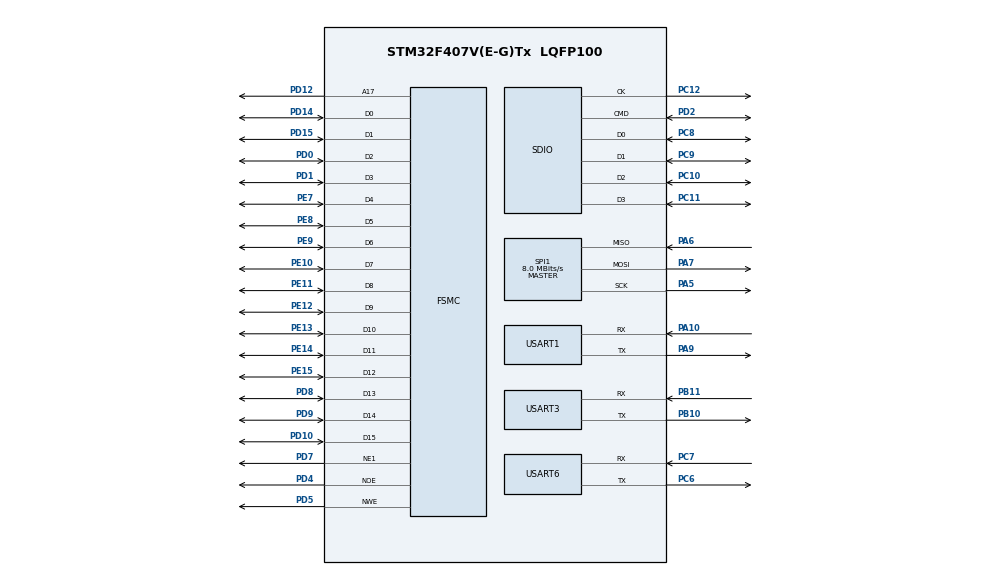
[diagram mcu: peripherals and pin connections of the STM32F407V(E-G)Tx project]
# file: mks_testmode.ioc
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Dma.Request0=SDIO
Dma.SDIO.0.Direction=DMA_PERIPH_TO_MEMORY
Dma.SDIO.0.FIFOMode=DMA_FIFOMODE_ENABLE
Dma.SDIO.0.FIFOThreshold=DMA_FIFO_THRESHOLD_FULL
Dma.SDIO.0.Instance=DMA2_Stream3
Dma.SDIO.0.MemBurst=DMA_MBURST_INC4
Dma.SDIO.0.MemDataAlignment=DMA_MDATAALIGN_WORD
Dma.SDIO.0.MemInc=DMA_MINC_ENABLE
Dma.SDIO.0.Mode=DMA_PFCTRL
Dma.SDIO.0.PeriphBurst=DMA_PBURST_INC4
Dma.SDIO.0.PeriphDataAlignment=DMA_PDATAALIGN_WORD
Dma.SDIO.0.PeriphInc=DMA_PINC_DISABLE
Dma.SDIO.0.Priority=DMA_PRIORITY_LOW
FSMC.ExtendedMode1=FSMC_EXTENDED_MODE_DISABLE
Mcu.Family=STM32F4
Mcu.Name=STM32F407V(E-G)Tx
Mcu.Package=LQFP100
NVIC.DMA2_Stream3_IRQn=true\:0\:0\:false\:false\:true\:false\:true
NVIC.PriorityGroup=NVIC_PRIORITYGROUP_4
PA10.Mode=Asynchronous
PA10.Signal=USART1_RX
PA5.Mode=Full_Duplex_Master
PA5.Signal=SPI1_SCK
PA6.Mode=Full_Duplex_Master
PA6.Signal=SPI1_MISO
PA7.Mode=Full_Duplex_Master
PA7.Signal=SPI1_MOSI
PA9.Mode=Asynchronous
PA9.Signal=USART1_TX
PB10.Mode=Asynchronous
PB10.Signal=USART3_TX
PB11.Mode=Asynchronous
PB11.Signal=USART3_RX
PC10.Mode=SD_4_bits_Wide_bus
PC10.Signal=SDIO_D2
PC11.Mode=SD_4_bits_Wide_bus
PC11.Signal=SDIO_D3
PC12.Mode=SD_4_bits_Wide_bus
PC12.Signal=SDIO_CK
PC6.Mode=Asynchronous
PC6.Signal=USART6_TX
PC7.Mode=Asynchronous
PC7.Signal=USART6_RX
PC8.Mode=SD_4_bits_Wide_bus
PC8.Signal=SDIO_D0
PC9.Mode=SD_4_bits_Wide_bus
PC9.Signal=SDIO_D1
PD0.Mode=16b-d1
PD0.Signal=FSMC_D2
PD1.Mode=16b-d1
PD1.Signal=FSMC_D3
PD10.Mode=16b-d1
PD10.Signal=FSMC_D15
PD12.Mode=A17_1
PD12.Signal=FSMC_A17
PD14.Mode=16b-d1
PD14.Signal=FSMC_D0
PD15.Mode=16b-d1
PD15.Signal=FSMC_D1
PD2.Mode=SD_4_bits_Wide_bus
PD2.Signal=SDIO_CMD
PD4.Mode=Lcd1
PD4.Signal=FSMC_NOE
PD5.Mode=Lcd1
PD5.Signal=FSMC_NWE
PD7.Mode=NorPsramChipSelect1_1
PD7.Signal=FSMC_NE1
PD8.Mode=16b-d1
PD8.Signal=FSMC_D13
PD9.Mode=16b-d1
PD9.Signal=FSMC_D14
PE10.Mode=16b-d1
PE10.Signal=FSMC_D7
PE11.Mode=16b-d1
PE11.Signal=FSMC_D8
PE12.Mode=16b-d1
PE12.Signal=FSMC_D9
PE13.Mode=16b-d1
PE13.Signal=FSMC_D10
PE14.Mode=16b-d1
PE14.Signal=FSMC_D11
PE15.Mode=16b-d1
PE15.Signal=FSMC_D12
PE7.Mode=16b-d1
PE7.Signal=FSMC_D4
PE8.Mode=16b-d1
PE8.Signal=FSMC_D5
PE9.Mode=16b-d1
PE9.Signal=FSMC_D6
PH0-OSC_IN.Mode=HSE-External-Oscillator
PH0-OSC_IN.Signal=RCC_OSC_IN
PH1-OSC_OUT.Mode=HSE-External-Oscillator
PH1-OSC_OUT.Signal=RCC_OSC_OUT
ProjectManager.HeapSize=0x200
ProjectManager.StackSize=0x400
ProjectManager.TargetToolchain=Makefile
RCC.AHBFreq_Value=16000000
RCC.APB1Freq_Value=16000000
RCC.APB2Freq_Value=16000000
RCC.CortexFreq_Value=16000000
RCC.HSE_VALUE=25000000
RCC.HSI_VALUE=16000000
RCC.SYSCLKFreq_VALUE=16000000
RCC.VCOOutputFreq_Value=192000000
SPI1.CalculateBaudRate=8.0 MBits/s
SPI1.Direction=SPI_DIRECTION_2LINES
SPI1.Mode=SPI_MODE_MASTER
SPI1.VirtualType=VM_MASTER
USART1.VirtualMode=VM_ASYNC
USART3.VirtualMode=VM_ASYNC
USART6.VirtualMode=VM_ASYNC
board=custom

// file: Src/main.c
#include "main.h"
#include "stm32_adafruit_lcd.h"
#include "stm32_adafruit_ts.h"
#include "ts.h"
#include "lcd_screen.h"
#include <XPT2046_touch.h>
SD_HandleTypeDef hsd;
DMA_HandleTypeDef hdma_sdio;

SPI_HandleTypeDef hspi1;

UART_HandleTypeDef huart1;
UART_HandleTypeDef huart3;
UART_HandleTypeDef huart6;

SRAM_HandleTypeDef hsram1;

TIM_HandleTypeDef htim6;

void SystemClock_Config(void);
static void MX_GPIO_Init(void);
static void MX_DMA_Init(void);
static void MX_FSMC_Init(void);
static void MX_SDIO_SD_Init(void);
static void MX_SPI1_Init(void);
static void MX_USART1_UART_Init(void);
static void MX_USART3_UART_Init(void);
static void MX_USART6_UART_Init(void);

#define LCD_INIT_CLEAR 1

 #define TEXT "testing"

 //Vars
 char txt[60];

#define FONT_USED Font8

char X_POS;
uint16_t tsx, tsy, dx, dy, c;

void display_line_numbers(void)
{
 // BSP_LCD_Clear(LCD_COLOR_BLACK);
 //Display Line numbers
  for (int line_nr=1;line_nr<27;line_nr++)
    {
      BSP_LCD_SetTextColor(LCD_COLOR_BLACK);
      snprintf(txt, 60,"");
      BSP_LCD_DisplayStringAt(0,BSP_LCD_GetYSize()-(line_nr * CHARSIZEY),(uint8_t *)txt,CENTER_MODE);

      BSP_LCD_SetTextColor(LCD_COLOR_RED+(line_nr*1));
      snprintf(txt, 60, "   Touch X %d,Touch Y %d,State %d ",dx,dy, XPT2046_TouchPressed());
      BSP_LCD_DisplayStringAt(0,BSP_LCD_GetYSize()-(line_nr * CHARSIZEY),(uint8_t *)txt,CENTER_MODE);

   }
}

char SECOND_COUNT=0;
char REFRESH=0;

int main(void)
{

  HAL_Init();
  SystemClock_Config();

  MX_GPIO_Init();
  MX_DMA_Init();
  MX_FSMC_Init();
  MX_SDIO_SD_Init();
  MX_SPI1_Init();
  MX_USART1_UART_Init();
  MX_USART3_UART_Init();
  MX_USART6_UART_Init();

  int error_lcd = BSP_LCD_Init();
  if (error_lcd != LCD_OK )
  {
    printf("lcd error %d",error_lcd);
  }

  BSP_LCD_SetTextColor(LCD_COLOR_RED);
  BSP_LCD_SetFont(&Font12);
  //Beyond Here there be dragons and main code
  //mainApp();
mainApp();
  while (1)
  {
  HAL_Delay(100);
  if(XPT2046_TouchPressed()) {

    XPT2046_TouchGetCoordinates(&dx,&dy);

  }
  if (REFRESH>10)
  {
  // display_line_numbers();
    REFRESH=0;
  }
  if (SECOND_COUNT>200)
  {
    X_POS++;
    SECOND_COUNT=0;
  }
  SECOND_COUNT++;
  REFRESH++;
  display_line_numbers();
  }

}

void SystemClock_Config(void)
{
  RCC_OscInitTypeDef RCC_OscInitStruct;
 RCC_ClkInitTypeDef RCC_ClkInitStruct;
 RCC_PeriphCLKInitTypeDef PeriphClkInitStruct;

    /**Configure the main internal regulator output voltage
    */
  __HAL_RCC_PWR_CLK_ENABLE();

  __HAL_PWR_VOLTAGESCALING_CONFIG(PWR_REGULATOR_VOLTAGE_SCALE1);

    /**Initializes the CPU, AHB and APB busses clocks
    */
  RCC_OscInitStruct.OscillatorType = RCC_OSCILLATORTYPE_HSE;
  RCC_OscInitStruct.HSEState = RCC_HSE_ON;
  RCC_OscInitStruct.PLL.PLLState = RCC_PLL_ON;
  RCC_OscInitStruct.PLL.PLLSource = RCC_PLLSOURCE_HSE;
  RCC_OscInitStruct.PLL.PLLM = 4;
  RCC_OscInitStruct.PLL.PLLN = 168;
  RCC_OscInitStruct.PLL.PLLP = RCC_PLLP_DIV2;
  RCC_OscInitStruct.PLL.PLLQ = 7;
  if (HAL_RCC_OscConfig(&RCC_OscInitStruct) != HAL_OK)
  {
    Error_Handler();
  }

    /**Initializes the CPU, AHB and APB busses clocks
    */
  RCC_ClkInitStruct.ClockType = RCC_CLOCKTYPE_HCLK|RCC_CLOCKTYPE_SYSCLK
                              |RCC_CLOCKTYPE_PCLK1|RCC_CLOCKTYPE_PCLK2;
  RCC_ClkInitStruct.SYSCLKSource = RCC_SYSCLKSOURCE_PLLCLK;
  RCC_ClkInitStruct.AHBCLKDivider = RCC_SYSCLK_DIV1;
  RCC_ClkInitStruct.APB1CLKDivider = RCC_HCLK_DIV4;
  RCC_ClkInitStruct.APB2CLKDivider = RCC_HCLK_DIV2;

  if (HAL_RCC_ClockConfig(&RCC_ClkInitStruct, FLASH_LATENCY_5) != HAL_OK)
  {
    Error_Handler();
  }

  PeriphClkInitStruct.PeriphClockSelection = RCC_PERIPHCLK_RTC;
  PeriphClkInitStruct.RTCClockSelection = RCC_RTCCLKSOURCE_LSI;
  if (HAL_RCCEx_PeriphCLKConfig(&PeriphClkInitStruct) != HAL_OK)
  {
    Error_Handler();
  }

    /**Configure the Systick interrupt time
    */
  HAL_SYSTICK_Config(HAL_RCC_GetHCLKFreq()/1000);

    /**Configure the Systick
    */
  HAL_SYSTICK_CLKSourceConfig(SYSTICK_CLKSOURCE_HCLK);

  /* SysTick_IRQn interrupt configuration */
  HAL_NVIC_SetPriority(SysTick_IRQn, 0, 0);
}

static void MX_SDIO_SD_Init(void)
{

  hsd.Instance = SDIO;
  hsd.Init.ClockEdge = SDIO_CLOCK_EDGE_RISING;
  hsd.Init.ClockBypass = SDIO_CLOCK_BYPASS_DISABLE;
  hsd.Init.ClockPowerSave = SDIO_CLOCK_POWER_SAVE_DISABLE;
  hsd.Init.BusWide = SDIO_BUS_WIDE_1B;
  hsd.Init.HardwareFlowControl = SDIO_HARDWARE_FLOW_CONTROL_DISABLE;
  hsd.Init.ClockDiv = 0;
  if (HAL_SD_Init(&hsd) != HAL_OK)
  {
    Error_Handler();
  }
  if (HAL_SD_ConfigWideBusOperation(&hsd, SDIO_BUS_WIDE_4B) != HAL_OK)
  {
    Error_Handler();
  }

}

static void MX_SPI1_Init(void)
{

  hspi1.Instance = SPI1;
  hspi1.Init.Mode = SPI_MODE_MASTER;
  hspi1.Init.Direction = SPI_DIRECTION_2LINES;
  hspi1.Init.DataSize = SPI_DATASIZE_8BIT;
  hspi1.Init.CLKPolarity = SPI_POLARITY_LOW;
  hspi1.Init.CLKPhase = SPI_PHASE_1EDGE;
  hspi1.Init.NSS = SPI_NSS_SOFT;
  hspi1.Init.BaudRatePrescaler = SPI_BAUDRATEPRESCALER_256;
  hspi1.Init.FirstBit = SPI_FIRSTBIT_MSB;
  hspi1.Init.TIMode = SPI_TIMODE_DISABLE;
  hspi1.Init.CRCCalculation = SPI_CRCCALCULATION_DISABLE;
  hspi1.Init.CRCPolynomial = 10;
  if (HAL_SPI_Init(&hspi1) != HAL_OK)
  {
    Error_Handler();
  }

}

static void MX_USART1_UART_Init(void)
{

  huart1.Instance = USART1;
  huart1.Init.BaudRate = 115200;
  huart1.Init.WordLength = UART_WORDLENGTH_8B;
  huart1.Init.StopBits = UART_STOPBITS_1;
  huart1.Init.Parity = UART_PARITY_NONE;
  huart1.Init.Mode = UART_MODE_TX_RX;
  huart1.Init.HwFlowCtl = UART_HWCONTROL_NONE;
  huart1.Init.OverSampling = UART_OVERSAMPLING_16;
  if (HAL_UART_Init(&huart1) != HAL_OK)
  {
    Error_Handler();
  }

}

static void MX_USART3_UART_Init(void)
{

  huart3.Instance = USART3;
  huart3.Init.BaudRate = 115200;
  huart3.Init.WordLength = UART_WORDLENGTH_8B;
  huart3.Init.StopBits = UART_STOPBITS_1;
  huart3.Init.Parity = UART_PARITY_NONE;
  huart3.Init.Mode = UART_MODE_TX_RX;
  huart3.Init.HwFlowCtl = UART_HWCONTROL_NONE;
  huart3.Init.OverSampling = UART_OVERSAMPLING_16;
  if (HAL_UART_Init(&huart3) != HAL_OK)
  {
    Error_Handler();
  }

}

static void MX_USART6_UART_Init(void)
{

  huart6.Instance = USART6;
  huart6.Init.BaudRate = 115200;
  huart6.Init.WordLength = UART_WORDLENGTH_8B;
  huart6.Init.StopBits = UART_STOPBITS_1;
  huart6.Init.Parity = UART_PARITY_NONE;
  huart6.Init.Mode = UART_MODE_TX_RX;
  huart6.Init.HwFlowCtl = UART_HWCONTROL_NONE;
  huart6.Init.OverSampling = UART_OVERSAMPLING_16;
  if (HAL_UART_Init(&huart6) != HAL_OK)
  {
    Error_Handler();
  }

}

static void MX_DMA_Init(void)
{

  /* DMA controller clock enable */
  __HAL_RCC_DMA2_CLK_ENABLE();

  /* DMA interrupt init */
  /* DMA2_Stream3_IRQn interrupt configuration */
  HAL_NVIC_SetPriority(DMA2_Stream3_IRQn, 0, 0);
  HAL_NVIC_EnableIRQ(DMA2_Stream3_IRQn);

}

static void MX_GPIO_Init(void)
{
GPIO_InitTypeDef GPIO_InitStruct = {0};
  /* GPIO Ports Clock Enable */
  __HAL_RCC_GPIOH_CLK_ENABLE();
  __HAL_RCC_GPIOA_CLK_ENABLE();
  __HAL_RCC_GPIOE_CLK_ENABLE();
  __HAL_RCC_GPIOB_CLK_ENABLE();
  __HAL_RCC_GPIOD_CLK_ENABLE();
  __HAL_RCC_GPIOC_CLK_ENABLE();

 /*Configure GPIO pin Output Level */
  HAL_GPIO_WritePin(GPIOA, GPIO_PIN_1, GPIO_PIN_RESET);

  /*Configure GPIO pin Output Level */
  HAL_GPIO_WritePin(GPIOB, GPIO_PIN_0, GPIO_PIN_RESET);

  /*Configure GPIO pin : PA1 */
  GPIO_InitStruct.Pin = GPIO_PIN_1|GPIO_PIN_2;
  GPIO_InitStruct.Mode = GPIO_MODE_OUTPUT_PP;
  GPIO_InitStruct.Pull = GPIO_NOPULL;
  GPIO_InitStruct.Speed = GPIO_SPEED_FREQ_LOW;
  HAL_GPIO_Init(GPIOA, &GPIO_InitStruct);

  /*Configure GPIO pin : PB0 */
  GPIO_InitStruct.Pin = GPIO_PIN_0| GPIO_PIN_9;
  GPIO_InitStruct.Mode = GPIO_MODE_OUTPUT_PP;
  GPIO_InitStruct.Pull = GPIO_PULLUP;
  GPIO_InitStruct.Speed = GPIO_SPEED_FREQ_LOW;
  HAL_GPIO_Init(GPIOB, &GPIO_InitStruct);

  //Configure TP_INT Pin
 GPIO_InitStruct.Pin = GPIO_PIN_5;
 GPIO_InitStruct.Mode = GPIO_MODE_INPUT;
 GPIO_InitStruct.Pull = GPIO_NOPULL;
 GPIO_InitStruct.Speed = GPIO_SPEED_FREQ_VERY_HIGH;
 HAL_GPIO_Init(GPIOC, &GPIO_InitStruct);

//Set CS for eeprom flash to CS as device uses /CS
HAL_GPIO_WritePin(GPIOB,GPIO_PIN_9,GPIO_PIN_SET);
}

/* FSMC initialization function */
static void MX_FSMC_Init(void)
{

    FSMC_NORSRAM_TimingTypeDef Timing;

  /** Perform the SRAM1 memory initialization sequence
  */
  hsram1.Instance = FSMC_NORSRAM_DEVICE;
  hsram1.Extended = FSMC_NORSRAM_EXTENDED_DEVICE;
  /* hsram1.Init */
  hsram1.Init.NSBank = FSMC_NORSRAM_BANK1;
  hsram1.Init.DataAddressMux = FSMC_DATA_ADDRESS_MUX_DISABLE;
  hsram1.Init.MemoryType = FSMC_MEMORY_TYPE_SRAM;
  hsram1.Init.MemoryDataWidth = FSMC_NORSRAM_MEM_BUS_WIDTH_16;
  hsram1.Init.BurstAccessMode = FSMC_BURST_ACCESS_MODE_DISABLE;
  hsram1.Init.WaitSignalPolarity = FSMC_WAIT_SIGNAL_POLARITY_LOW;
  hsram1.Init.WrapMode = FSMC_WRAP_MODE_DISABLE;
  hsram1.Init.WaitSignalActive = FSMC_WAIT_TIMING_BEFORE_WS;
  hsram1.Init.WriteOperation = FSMC_WRITE_OPERATION_ENABLE;
  hsram1.Init.WaitSignal = FSMC_WAIT_SIGNAL_DISABLE;
  hsram1.Init.ExtendedMode = FSMC_EXTENDED_MODE_DISABLE;
  hsram1.Init.AsynchronousWait = FSMC_ASYNCHRONOUS_WAIT_DISABLE;
  hsram1.Init.WriteBurst = FSMC_WRITE_BURST_DISABLE;
  hsram1.Init.PageSize = FSMC_PAGE_SIZE_NONE;
  /* Timing */
  Timing.AddressSetupTime = 5;
  Timing.AddressHoldTime = 15;
  Timing.DataSetupTime = 8;
  Timing.BusTurnAroundDuration = 1;
  Timing.CLKDivision = 16;
  Timing.DataLatency = 17;
  Timing.AccessMode = FSMC_ACCESS_MODE_A;
  /* ExtTiming */

  if (HAL_SRAM_Init(&hsram1, &Timing, NULL) != HAL_OK)
  {
    Error_Handler( );
  }

}

void HAL_TIM_PeriodElapsedCallback(TIM_HandleTypeDef *htim)
{
  if (htim->Instance == TIM6) {
    HAL_IncTick();
  }
}

void Error_Handler(void)
{

}

/************************ (C) COPYRIGHT STMicroelectronics *****END OF FILE****/
